VERSION 5.7 ;
  NOWIREEXTENSIONATPIN ON ;
  DIVIDERCHAR "/" ;
  BUSBITCHARS "[]" ;
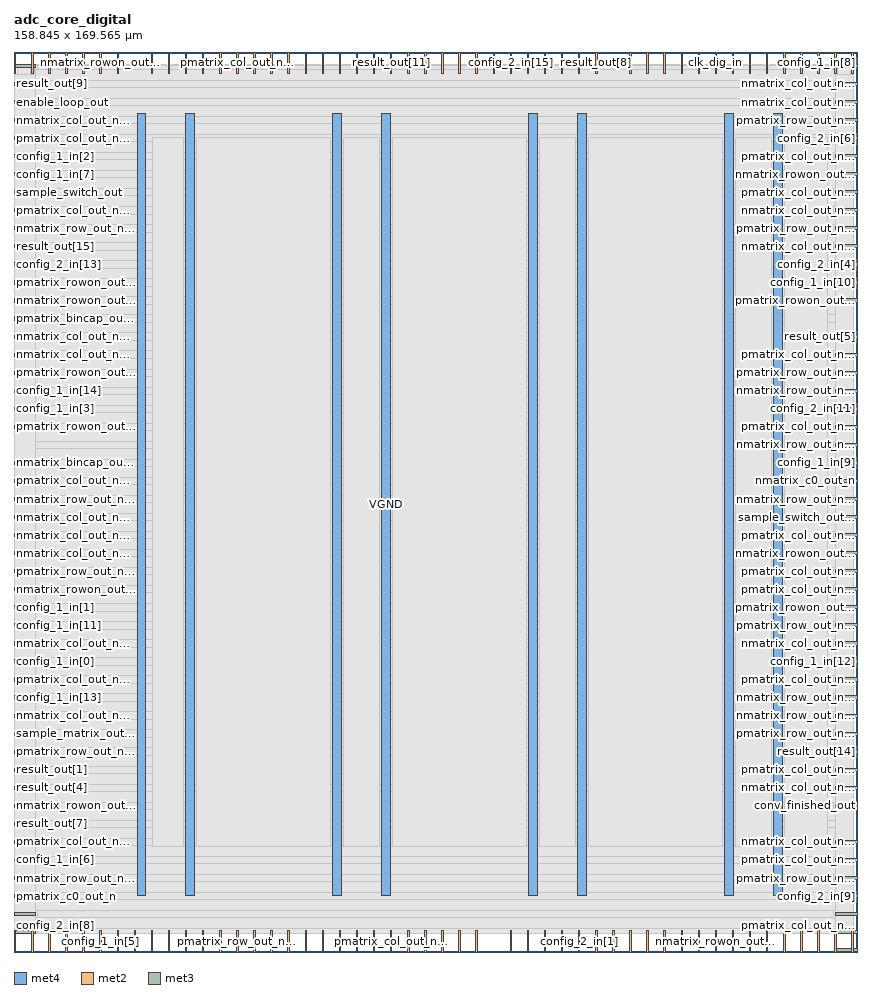
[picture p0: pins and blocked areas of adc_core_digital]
MACRO adc_core_digital
  CLASS BLOCK ;
  FOREIGN adc_core_digital ;
  ORIGIN 0.000 0.000 ;
  SIZE 158.845 BY 169.565 ;
  PIN VGND
    DIRECTION INOUT ;
    USE GROUND ;
    PORT
      LAYER met4 ;
        RECT 32.400 10.640 34.000 158.000 ;
    END
    PORT
      LAYER met4 ;
        RECT 69.315 10.640 70.915 158.000 ;
    END
    PORT
      LAYER met4 ;
        RECT 106.230 10.640 107.830 158.000 ;
    END
    PORT
      LAYER met4 ;
        RECT 143.145 10.640 144.745 158.000 ;
    END
  END VGND
  PIN VPWR
    DIRECTION INOUT ;
    USE POWER ;
    PORT
      LAYER met4 ;
        RECT 23.175 10.640 24.775 158.000 ;
    END
    PORT
      LAYER met4 ;
        RECT 60.090 10.640 61.690 158.000 ;
    END
    PORT
      LAYER met4 ;
        RECT 97.005 10.640 98.605 158.000 ;
    END
    PORT
      LAYER met4 ;
        RECT 133.920 10.640 135.520 158.000 ;
    END
  END VPWR
  PIN clk_dig_in
    DIRECTION INPUT ;
    USE SIGNAL ;
    PORT
      LAYER met2 ;
        RECT 132.110 165.565 132.390 169.565 ;
    END
  END clk_dig_in
  PIN comparator_in
    DIRECTION INPUT ;
    USE SIGNAL ;
    PORT
      LAYER met2 ;
        RECT 51.610 165.565 51.890 169.565 ;
    END
  END comparator_in
  PIN config_1_in[0]
    DIRECTION INPUT ;
    USE SIGNAL ;
    PORT
      LAYER met3 ;
        RECT 0.000 54.440 4.000 55.040 ;
    END
  END config_1_in[0]
  PIN config_1_in[10]
    DIRECTION INPUT ;
    USE SIGNAL ;
    PORT
      LAYER met3 ;
        RECT 154.845 125.840 158.845 126.440 ;
    END
  END config_1_in[10]
  PIN config_1_in[11]
    DIRECTION INPUT ;
    USE SIGNAL ;
    PORT
      LAYER met3 ;
        RECT 0.000 61.240 4.000 61.840 ;
    END
  END config_1_in[11]
  PIN config_1_in[12]
    DIRECTION INPUT ;
    USE SIGNAL ;
    PORT
      LAYER met3 ;
        RECT 154.845 54.440 158.845 55.040 ;
    END
  END config_1_in[12]
  PIN config_1_in[13]
    DIRECTION INPUT ;
    USE SIGNAL ;
    PORT
      LAYER met3 ;
        RECT 0.000 47.640 4.000 48.240 ;
    END
  END config_1_in[13]
  PIN config_1_in[14]
    DIRECTION INPUT ;
    USE SIGNAL ;
    PORT
      LAYER met3 ;
        RECT 0.000 105.440 4.000 106.040 ;
    END
  END config_1_in[14]
  PIN config_1_in[15]
    DIRECTION INPUT ;
    USE SIGNAL ;
    PORT
      LAYER met2 ;
        RECT 35.510 165.565 35.790 169.565 ;
    END
  END config_1_in[15]
  PIN config_1_in[1]
    DIRECTION INPUT ;
    USE SIGNAL ;
    PORT
      LAYER met3 ;
        RECT 0.000 64.640 4.000 65.240 ;
    END
  END config_1_in[1]
  PIN config_1_in[2]
    DIRECTION INPUT ;
    USE SIGNAL ;
    PORT
      LAYER met3 ;
        RECT 0.000 149.640 4.000 150.240 ;
    END
  END config_1_in[2]
  PIN config_1_in[3]
    DIRECTION INPUT ;
    USE SIGNAL ;
    PORT
      LAYER met3 ;
        RECT 0.000 102.040 4.000 102.640 ;
    END
  END config_1_in[3]
  PIN config_1_in[4]
    DIRECTION INPUT ;
    USE SIGNAL ;
    PORT
      LAYER met2 ;
        RECT 29.070 165.565 29.350 169.565 ;
    END
  END config_1_in[4]
  PIN config_1_in[5]
    DIRECTION INPUT ;
    USE SIGNAL ;
    PORT
      LAYER met2 ;
        RECT 16.190 0.000 16.470 4.000 ;
    END
  END config_1_in[5]
  PIN config_1_in[6]
    DIRECTION INPUT ;
    USE SIGNAL ;
    PORT
      LAYER met3 ;
        RECT 0.000 17.040 4.000 17.640 ;
    END
  END config_1_in[6]
  PIN config_1_in[7]
    DIRECTION INPUT ;
    USE SIGNAL ;
    PORT
      LAYER met3 ;
        RECT 0.000 146.240 4.000 146.840 ;
    END
  END config_1_in[7]
  PIN config_1_in[8]
    DIRECTION INPUT ;
    USE SIGNAL ;
    PORT
      LAYER met2 ;
        RECT 154.650 165.565 154.930 169.565 ;
    END
  END config_1_in[8]
  PIN config_1_in[9]
    DIRECTION INPUT ;
    USE SIGNAL ;
    PORT
      LAYER met3 ;
        RECT 154.845 91.840 158.845 92.440 ;
    END
  END config_1_in[9]
  PIN config_2_in[0]
    DIRECTION INPUT ;
    USE SIGNAL ;
    PORT
      LAYER met2 ;
        RECT 38.730 0.000 39.010 4.000 ;
    END
  END config_2_in[0]
  PIN config_2_in[10]
    DIRECTION INPUT ;
    USE SIGNAL ;
    PORT
      LAYER met2 ;
        RECT 64.490 165.565 64.770 169.565 ;
    END
  END config_2_in[10]
  PIN config_2_in[11]
    DIRECTION INPUT ;
    USE SIGNAL ;
    PORT
      LAYER met3 ;
        RECT 154.845 102.040 158.845 102.640 ;
    END
  END config_2_in[11]
  PIN config_2_in[12]
    DIRECTION INPUT ;
    USE SIGNAL ;
    PORT
      LAYER met3 ;
        RECT 154.845 0.040 158.845 0.640 ;
    END
  END config_2_in[12]
  PIN config_2_in[13]
    DIRECTION INPUT ;
    USE SIGNAL ;
    PORT
      LAYER met3 ;
        RECT 0.000 129.240 4.000 129.840 ;
    END
  END config_2_in[13]
  PIN config_2_in[14]
    DIRECTION INPUT ;
    USE SIGNAL ;
    PORT
      LAYER met2 ;
        RECT 51.610 0.000 51.890 4.000 ;
    END
  END config_2_in[14]
  PIN config_2_in[15]
    DIRECTION INPUT ;
    USE SIGNAL ;
    PORT
      LAYER met2 ;
        RECT 93.470 165.565 93.750 169.565 ;
    END
  END config_2_in[15]
  PIN config_2_in[1]
    DIRECTION INPUT ;
    USE SIGNAL ;
    PORT
      LAYER met2 ;
        RECT 106.350 0.000 106.630 4.000 ;
    END
  END config_2_in[1]
  PIN config_2_in[2]
    DIRECTION INPUT ;
    USE SIGNAL ;
    PORT
      LAYER met2 ;
        RECT 83.810 165.565 84.090 169.565 ;
    END
  END config_2_in[2]
  PIN config_2_in[3]
    DIRECTION INPUT ;
    USE SIGNAL ;
    PORT
      LAYER met2 ;
        RECT 151.430 0.000 151.710 4.000 ;
    END
  END config_2_in[3]
  PIN config_2_in[4]
    DIRECTION INPUT ;
    USE SIGNAL ;
    PORT
      LAYER met3 ;
        RECT 154.845 129.240 158.845 129.840 ;
    END
  END config_2_in[4]
  PIN config_2_in[5]
    DIRECTION INPUT ;
    USE SIGNAL ;
    PORT
      LAYER met2 ;
        RECT 67.710 165.565 67.990 169.565 ;
    END
  END config_2_in[5]
  PIN config_2_in[6]
    DIRECTION INPUT ;
    USE SIGNAL ;
    PORT
      LAYER met3 ;
        RECT 154.845 153.040 158.845 153.640 ;
    END
  END config_2_in[6]
  PIN config_2_in[7]
    DIRECTION INPUT ;
    USE SIGNAL ;
    PORT
      LAYER met2 ;
        RECT 135.330 165.565 135.610 169.565 ;
    END
  END config_2_in[7]
  PIN config_2_in[8]
    DIRECTION INPUT ;
    USE SIGNAL ;
    PORT
      LAYER met3 ;
        RECT 0.000 3.440 4.000 4.040 ;
    END
  END config_2_in[8]
  PIN config_2_in[9]
    DIRECTION INPUT ;
    USE SIGNAL ;
    PORT
      LAYER met3 ;
        RECT 154.845 10.240 158.845 10.840 ;
    END
  END config_2_in[9]
  PIN conv_finished_out
    DIRECTION OUTPUT TRISTATE ;
    USE SIGNAL ;
    PORT
      LAYER met3 ;
        RECT 154.845 27.240 158.845 27.840 ;
    END
  END conv_finished_out
  PIN enable_loop_out
    DIRECTION OUTPUT TRISTATE ;
    USE SIGNAL ;
    PORT
      LAYER met3 ;
        RECT 0.000 159.840 4.000 160.440 ;
    END
  END enable_loop_out
  PIN nmatrix_bincap_out_n[0]
    DIRECTION OUTPUT TRISTATE ;
    USE SIGNAL ;
    PORT
      LAYER met2 ;
        RECT 6.530 165.565 6.810 169.565 ;
    END
  END nmatrix_bincap_out_n[0]
  PIN nmatrix_bincap_out_n[1]
    DIRECTION OUTPUT TRISTATE ;
    USE SIGNAL ;
    PORT
      LAYER met3 ;
        RECT 0.000 91.840 4.000 92.440 ;
    END
  END nmatrix_bincap_out_n[1]
  PIN nmatrix_bincap_out_n[2]
    DIRECTION OUTPUT TRISTATE ;
    USE SIGNAL ;
    PORT
      LAYER met3 ;
        RECT 0.000 6.840 4.000 7.440 ;
    END
  END nmatrix_bincap_out_n[2]
  PIN nmatrix_c0_out_n
    DIRECTION OUTPUT TRISTATE ;
    USE SIGNAL ;
    PORT
      LAYER met3 ;
        RECT 154.845 88.440 158.845 89.040 ;
    END
  END nmatrix_c0_out_n
  PIN nmatrix_col_out_n[0]
    DIRECTION OUTPUT TRISTATE ;
    USE SIGNAL ;
    PORT
      LAYER met3 ;
        RECT 0.000 81.640 4.000 82.240 ;
    END
  END nmatrix_col_out_n[0]
  PIN nmatrix_col_out_n[10]
    DIRECTION OUTPUT TRISTATE ;
    USE SIGNAL ;
    PORT
      LAYER met3 ;
        RECT 0.000 166.640 4.000 167.240 ;
    END
  END nmatrix_col_out_n[10]
  PIN nmatrix_col_out_n[11]
    DIRECTION OUTPUT TRISTATE ;
    USE SIGNAL ;
    PORT
      LAYER met3 ;
        RECT 0.000 156.440 4.000 157.040 ;
    END
  END nmatrix_col_out_n[11]
  PIN nmatrix_col_out_n[12]
    DIRECTION OUTPUT TRISTATE ;
    USE SIGNAL ;
    PORT
      LAYER met2 ;
        RECT 144.990 0.000 145.270 4.000 ;
    END
  END nmatrix_col_out_n[12]
  PIN nmatrix_col_out_n[13]
    DIRECTION OUTPUT TRISTATE ;
    USE SIGNAL ;
    PORT
      LAYER met3 ;
        RECT 0.000 112.240 4.000 112.840 ;
    END
  END nmatrix_col_out_n[13]
  PIN nmatrix_col_out_n[14]
    DIRECTION OUTPUT TRISTATE ;
    USE SIGNAL ;
    PORT
      LAYER met2 ;
        RECT 141.770 165.565 142.050 169.565 ;
    END
  END nmatrix_col_out_n[14]
  PIN nmatrix_col_out_n[15]
    DIRECTION OUTPUT TRISTATE ;
    USE SIGNAL ;
    PORT
      LAYER met3 ;
        RECT 154.845 57.840 158.845 58.440 ;
    END
  END nmatrix_col_out_n[15]
  PIN nmatrix_col_out_n[16]
    DIRECTION OUTPUT TRISTATE ;
    USE SIGNAL ;
    PORT
      LAYER met3 ;
        RECT 0.000 115.640 4.000 116.240 ;
    END
  END nmatrix_col_out_n[16]
  PIN nmatrix_col_out_n[17]
    DIRECTION OUTPUT TRISTATE ;
    USE SIGNAL ;
    PORT
      LAYER met3 ;
        RECT 154.845 20.440 158.845 21.040 ;
    END
  END nmatrix_col_out_n[17]
  PIN nmatrix_col_out_n[18]
    DIRECTION OUTPUT TRISTATE ;
    USE SIGNAL ;
    PORT
      LAYER met2 ;
        RECT 45.170 0.000 45.450 4.000 ;
    END
  END nmatrix_col_out_n[18]
  PIN nmatrix_col_out_n[19]
    DIRECTION OUTPUT TRISTATE ;
    USE SIGNAL ;
    PORT
      LAYER met3 ;
        RECT 0.000 44.240 4.000 44.840 ;
    END
  END nmatrix_col_out_n[19]
  PIN nmatrix_col_out_n[1]
    DIRECTION OUTPUT TRISTATE ;
    USE SIGNAL ;
    PORT
      LAYER met3 ;
        RECT 0.000 57.840 4.000 58.440 ;
    END
  END nmatrix_col_out_n[1]
  PIN nmatrix_col_out_n[20]
    DIRECTION OUTPUT TRISTATE ;
    USE SIGNAL ;
    PORT
      LAYER met3 ;
        RECT 154.845 132.640 158.845 133.240 ;
    END
  END nmatrix_col_out_n[20]
  PIN nmatrix_col_out_n[21]
    DIRECTION OUTPUT TRISTATE ;
    USE SIGNAL ;
    PORT
      LAYER met2 ;
        RECT 48.390 165.565 48.670 169.565 ;
    END
  END nmatrix_col_out_n[21]
  PIN nmatrix_col_out_n[22]
    DIRECTION OUTPUT TRISTATE ;
    USE SIGNAL ;
    PORT
      LAYER met3 ;
        RECT 154.845 163.240 158.845 163.840 ;
    END
  END nmatrix_col_out_n[22]
  PIN nmatrix_col_out_n[23]
    DIRECTION OUTPUT TRISTATE ;
    USE SIGNAL ;
    PORT
      LAYER met3 ;
        RECT 0.000 78.240 4.000 78.840 ;
    END
  END nmatrix_col_out_n[23]
  PIN nmatrix_col_out_n[24]
    DIRECTION OUTPUT TRISTATE ;
    USE SIGNAL ;
    PORT
      LAYER met2 ;
        RECT 12.970 0.000 13.250 4.000 ;
    END
  END nmatrix_col_out_n[24]
  PIN nmatrix_col_out_n[25]
    DIRECTION OUTPUT TRISTATE ;
    USE SIGNAL ;
    PORT
      LAYER met3 ;
        RECT 0.000 74.840 4.000 75.440 ;
    END
  END nmatrix_col_out_n[25]
  PIN nmatrix_col_out_n[26]
    DIRECTION OUTPUT TRISTATE ;
    USE SIGNAL ;
    PORT
      LAYER met2 ;
        RECT 77.370 165.565 77.650 169.565 ;
    END
  END nmatrix_col_out_n[26]
  PIN nmatrix_col_out_n[27]
    DIRECTION OUTPUT TRISTATE ;
    USE SIGNAL ;
    PORT
      LAYER met3 ;
        RECT 154.845 139.440 158.845 140.040 ;
    END
  END nmatrix_col_out_n[27]
  PIN nmatrix_col_out_n[28]
    DIRECTION OUTPUT TRISTATE ;
    USE SIGNAL ;
    PORT
      LAYER met2 ;
        RECT 54.830 165.565 55.110 169.565 ;
    END
  END nmatrix_col_out_n[28]
  PIN nmatrix_col_out_n[29]
    DIRECTION OUTPUT TRISTATE ;
    USE SIGNAL ;
    PORT
      LAYER met3 ;
        RECT 154.845 159.840 158.845 160.440 ;
    END
  END nmatrix_col_out_n[29]
  PIN nmatrix_col_out_n[2]
    DIRECTION OUTPUT TRISTATE ;
    USE SIGNAL ;
    PORT
      LAYER met2 ;
        RECT 9.750 165.565 10.030 169.565 ;
    END
  END nmatrix_col_out_n[2]
  PIN nmatrix_col_out_n[30]
    DIRECTION OUTPUT TRISTATE ;
    USE SIGNAL ;
    PORT
      LAYER met2 ;
        RECT 125.670 0.000 125.950 4.000 ;
    END
  END nmatrix_col_out_n[30]
  PIN nmatrix_col_out_n[31]
    DIRECTION OUTPUT TRISTATE ;
    USE SIGNAL ;
    PORT
      LAYER met2 ;
        RECT 138.550 165.565 138.830 169.565 ;
    END
  END nmatrix_col_out_n[31]
  PIN nmatrix_col_out_n[3]
    DIRECTION OUTPUT TRISTATE ;
    USE SIGNAL ;
    PORT
      LAYER met2 ;
        RECT 25.850 165.565 26.130 169.565 ;
    END
  END nmatrix_col_out_n[3]
  PIN nmatrix_col_out_n[4]
    DIRECTION OUTPUT TRISTATE ;
    USE SIGNAL ;
    PORT
      LAYER met2 ;
        RECT 74.150 0.000 74.430 4.000 ;
    END
  END nmatrix_col_out_n[4]
  PIN nmatrix_col_out_n[5]
    DIRECTION OUTPUT TRISTATE ;
    USE SIGNAL ;
    PORT
      LAYER met2 ;
        RECT 128.890 0.000 129.170 4.000 ;
    END
  END nmatrix_col_out_n[5]
  PIN nmatrix_col_out_n[6]
    DIRECTION OUTPUT TRISTATE ;
    USE SIGNAL ;
    PORT
      LAYER met3 ;
        RECT 154.845 30.640 158.845 31.240 ;
    END
  END nmatrix_col_out_n[6]
  PIN nmatrix_col_out_n[7]
    DIRECTION OUTPUT TRISTATE ;
    USE SIGNAL ;
    PORT
      LAYER met2 ;
        RECT 122.450 0.000 122.730 4.000 ;
    END
  END nmatrix_col_out_n[7]
  PIN nmatrix_col_out_n[8]
    DIRECTION OUTPUT TRISTATE ;
    USE SIGNAL ;
    PORT
      LAYER met2 ;
        RECT 61.270 0.000 61.550 4.000 ;
    END
  END nmatrix_col_out_n[8]
  PIN nmatrix_col_out_n[9]
    DIRECTION OUTPUT TRISTATE ;
    USE SIGNAL ;
    PORT
      LAYER met3 ;
        RECT 154.845 166.640 158.845 167.240 ;
    END
  END nmatrix_col_out_n[9]
  PIN nmatrix_row_out_n[0]
    DIRECTION OUTPUT TRISTATE ;
    USE SIGNAL ;
    PORT
      LAYER met3 ;
        RECT 0.000 85.040 4.000 85.640 ;
    END
  END nmatrix_row_out_n[0]
  PIN nmatrix_row_out_n[10]
    DIRECTION OUTPUT TRISTATE ;
    USE SIGNAL ;
    PORT
      LAYER met3 ;
        RECT 154.845 47.640 158.845 48.240 ;
    END
  END nmatrix_row_out_n[10]
  PIN nmatrix_row_out_n[11]
    DIRECTION OUTPUT TRISTATE ;
    USE SIGNAL ;
    PORT
      LAYER met2 ;
        RECT 77.370 0.000 77.650 4.000 ;
    END
  END nmatrix_row_out_n[11]
  PIN nmatrix_row_out_n[12]
    DIRECTION OUTPUT TRISTATE ;
    USE SIGNAL ;
    PORT
      LAYER met3 ;
        RECT 154.845 85.040 158.845 85.640 ;
    END
  END nmatrix_row_out_n[12]
  PIN nmatrix_row_out_n[13]
    DIRECTION OUTPUT TRISTATE ;
    USE SIGNAL ;
    PORT
      LAYER met2 ;
        RECT 122.450 165.565 122.730 169.565 ;
    END
  END nmatrix_row_out_n[13]
  PIN nmatrix_row_out_n[14]
    DIRECTION OUTPUT TRISTATE ;
    USE SIGNAL ;
    PORT
      LAYER met2 ;
        RECT 45.170 165.565 45.450 169.565 ;
    END
  END nmatrix_row_out_n[14]
  PIN nmatrix_row_out_n[15]
    DIRECTION OUTPUT TRISTATE ;
    USE SIGNAL ;
    PORT
      LAYER met2 ;
        RECT 48.390 0.000 48.670 4.000 ;
    END
  END nmatrix_row_out_n[15]
  PIN nmatrix_row_out_n[1]
    DIRECTION OUTPUT TRISTATE ;
    USE SIGNAL ;
    PORT
      LAYER met3 ;
        RECT 0.000 136.040 4.000 136.640 ;
    END
  END nmatrix_row_out_n[1]
  PIN nmatrix_row_out_n[2]
    DIRECTION OUTPUT TRISTATE ;
    USE SIGNAL ;
    PORT
      LAYER met2 ;
        RECT 22.630 0.000 22.910 4.000 ;
    END
  END nmatrix_row_out_n[2]
  PIN nmatrix_row_out_n[3]
    DIRECTION OUTPUT TRISTATE ;
    USE SIGNAL ;
    PORT
      LAYER met2 ;
        RECT 83.810 0.000 84.090 4.000 ;
    END
  END nmatrix_row_out_n[3]
  PIN nmatrix_row_out_n[4]
    DIRECTION OUTPUT TRISTATE ;
    USE SIGNAL ;
    PORT
      LAYER met3 ;
        RECT 154.845 95.240 158.845 95.840 ;
    END
  END nmatrix_row_out_n[4]
  PIN nmatrix_row_out_n[5]
    DIRECTION OUTPUT TRISTATE ;
    USE SIGNAL ;
    PORT
      LAYER met3 ;
        RECT 154.845 44.240 158.845 44.840 ;
    END
  END nmatrix_row_out_n[5]
  PIN nmatrix_row_out_n[6]
    DIRECTION OUTPUT TRISTATE ;
    USE SIGNAL ;
    PORT
      LAYER met2 ;
        RECT 99.910 165.565 100.190 169.565 ;
    END
  END nmatrix_row_out_n[6]
  PIN nmatrix_row_out_n[7]
    DIRECTION OUTPUT TRISTATE ;
    USE SIGNAL ;
    PORT
      LAYER met3 ;
        RECT 154.845 105.440 158.845 106.040 ;
    END
  END nmatrix_row_out_n[7]
  PIN nmatrix_row_out_n[8]
    DIRECTION OUTPUT TRISTATE ;
    USE SIGNAL ;
    PORT
      LAYER met2 ;
        RECT 119.230 165.565 119.510 169.565 ;
    END
  END nmatrix_row_out_n[8]
  PIN nmatrix_row_out_n[9]
    DIRECTION OUTPUT TRISTATE ;
    USE SIGNAL ;
    PORT
      LAYER met3 ;
        RECT 0.000 13.640 4.000 14.240 ;
    END
  END nmatrix_row_out_n[9]
  PIN nmatrix_rowon_out_n[0]
    DIRECTION OUTPUT TRISTATE ;
    USE SIGNAL ;
    PORT
      LAYER met3 ;
        RECT 0.000 122.440 4.000 123.040 ;
    END
  END nmatrix_rowon_out_n[0]
  PIN nmatrix_rowon_out_n[10]
    DIRECTION OUTPUT TRISTATE ;
    USE SIGNAL ;
    PORT
      LAYER met2 ;
        RECT 132.110 0.000 132.390 4.000 ;
    END
  END nmatrix_rowon_out_n[10]
  PIN nmatrix_rowon_out_n[11]
    DIRECTION OUTPUT TRISTATE ;
    USE SIGNAL ;
    PORT
      LAYER met3 ;
        RECT 154.845 74.840 158.845 75.440 ;
    END
  END nmatrix_rowon_out_n[11]
  PIN nmatrix_rowon_out_n[12]
    DIRECTION OUTPUT TRISTATE ;
    USE SIGNAL ;
    PORT
      LAYER met2 ;
        RECT 144.990 165.565 145.270 169.565 ;
    END
  END nmatrix_rowon_out_n[12]
  PIN nmatrix_rowon_out_n[13]
    DIRECTION OUTPUT TRISTATE ;
    USE SIGNAL ;
    PORT
      LAYER met3 ;
        RECT 154.845 146.240 158.845 146.840 ;
    END
  END nmatrix_rowon_out_n[13]
  PIN nmatrix_rowon_out_n[14]
    DIRECTION OUTPUT TRISTATE ;
    USE SIGNAL ;
    PORT
      LAYER met2 ;
        RECT 6.530 0.000 6.810 4.000 ;
    END
  END nmatrix_rowon_out_n[14]
  PIN nmatrix_rowon_out_n[15]
    DIRECTION OUTPUT TRISTATE ;
    USE SIGNAL ;
    PORT
      LAYER met2 ;
        RECT 54.830 0.000 55.110 4.000 ;
    END
  END nmatrix_rowon_out_n[15]
  PIN nmatrix_rowon_out_n[1]
    DIRECTION OUTPUT TRISTATE ;
    USE SIGNAL ;
    PORT
      LAYER met2 ;
        RECT 116.010 165.565 116.290 169.565 ;
    END
  END nmatrix_rowon_out_n[1]
  PIN nmatrix_rowon_out_n[2]
    DIRECTION OUTPUT TRISTATE ;
    USE SIGNAL ;
    PORT
      LAYER met2 ;
        RECT 16.190 165.565 16.470 169.565 ;
    END
  END nmatrix_rowon_out_n[2]
  PIN nmatrix_rowon_out_n[3]
    DIRECTION OUTPUT TRISTATE ;
    USE SIGNAL ;
    PORT
      LAYER met2 ;
        RECT 64.490 0.000 64.770 4.000 ;
    END
  END nmatrix_rowon_out_n[3]
  PIN nmatrix_rowon_out_n[4]
    DIRECTION OUTPUT TRISTATE ;
    USE SIGNAL ;
    PORT
      LAYER met3 ;
        RECT 154.845 6.840 158.845 7.440 ;
    END
  END nmatrix_rowon_out_n[4]
  PIN nmatrix_rowon_out_n[5]
    DIRECTION OUTPUT TRISTATE ;
    USE SIGNAL ;
    PORT
      LAYER met2 ;
        RECT 138.550 0.000 138.830 4.000 ;
    END
  END nmatrix_rowon_out_n[5]
  PIN nmatrix_rowon_out_n[6]
    DIRECTION OUTPUT TRISTATE ;
    USE SIGNAL ;
    PORT
      LAYER met2 ;
        RECT 103.130 0.000 103.410 4.000 ;
    END
  END nmatrix_rowon_out_n[6]
  PIN nmatrix_rowon_out_n[7]
    DIRECTION OUTPUT TRISTATE ;
    USE SIGNAL ;
    PORT
      LAYER met3 ;
        RECT 0.000 68.040 4.000 68.640 ;
    END
  END nmatrix_rowon_out_n[7]
  PIN nmatrix_rowon_out_n[8]
    DIRECTION OUTPUT TRISTATE ;
    USE SIGNAL ;
    PORT
      LAYER met3 ;
        RECT 0.000 27.240 4.000 27.840 ;
    END
  END nmatrix_rowon_out_n[8]
  PIN nmatrix_rowon_out_n[9]
    DIRECTION OUTPUT TRISTATE ;
    USE SIGNAL ;
    PORT
      LAYER met2 ;
        RECT 125.670 165.565 125.950 169.565 ;
    END
  END nmatrix_rowon_out_n[9]
  PIN pmatrix_bincap_out_n[0]
    DIRECTION OUTPUT TRISTATE ;
    USE SIGNAL ;
    PORT
      LAYER met2 ;
        RECT 38.730 165.565 39.010 169.565 ;
    END
  END pmatrix_bincap_out_n[0]
  PIN pmatrix_bincap_out_n[1]
    DIRECTION OUTPUT TRISTATE ;
    USE SIGNAL ;
    PORT
      LAYER met2 ;
        RECT 135.330 0.000 135.610 4.000 ;
    END
  END pmatrix_bincap_out_n[1]
  PIN pmatrix_bincap_out_n[2]
    DIRECTION OUTPUT TRISTATE ;
    USE SIGNAL ;
    PORT
      LAYER met3 ;
        RECT 0.000 119.040 4.000 119.640 ;
    END
  END pmatrix_bincap_out_n[2]
  PIN pmatrix_c0_out_n
    DIRECTION OUTPUT TRISTATE ;
    USE SIGNAL ;
    PORT
      LAYER met3 ;
        RECT 0.000 10.240 4.000 10.840 ;
    END
  END pmatrix_c0_out_n
  PIN pmatrix_col_out_n[0]
    DIRECTION OUTPUT TRISTATE ;
    USE SIGNAL ;
    PORT
      LAYER met3 ;
        RECT 0.000 51.040 4.000 51.640 ;
    END
  END pmatrix_col_out_n[0]
  PIN pmatrix_col_out_n[10]
    DIRECTION OUTPUT TRISTATE ;
    USE SIGNAL ;
    PORT
      LAYER met3 ;
        RECT 154.845 149.640 158.845 150.240 ;
    END
  END pmatrix_col_out_n[10]
  PIN pmatrix_col_out_n[11]
    DIRECTION OUTPUT TRISTATE ;
    USE SIGNAL ;
    PORT
      LAYER met3 ;
        RECT 154.845 17.040 158.845 17.640 ;
    END
  END pmatrix_col_out_n[11]
  PIN pmatrix_col_out_n[12]
    DIRECTION OUTPUT TRISTATE ;
    USE SIGNAL ;
    PORT
      LAYER met3 ;
        RECT 154.845 68.040 158.845 68.640 ;
    END
  END pmatrix_col_out_n[12]
  PIN pmatrix_col_out_n[13]
    DIRECTION OUTPUT TRISTATE ;
    USE SIGNAL ;
    PORT
      LAYER met2 ;
        RECT 3.310 165.565 3.590 169.565 ;
    END
  END pmatrix_col_out_n[13]
  PIN pmatrix_col_out_n[14]
    DIRECTION OUTPUT TRISTATE ;
    USE SIGNAL ;
    PORT
      LAYER met3 ;
        RECT 154.845 98.640 158.845 99.240 ;
    END
  END pmatrix_col_out_n[14]
  PIN pmatrix_col_out_n[15]
    DIRECTION OUTPUT TRISTATE ;
    USE SIGNAL ;
    PORT
      LAYER met3 ;
        RECT 154.845 3.440 158.845 4.040 ;
    END
  END pmatrix_col_out_n[15]
  PIN pmatrix_col_out_n[16]
    DIRECTION OUTPUT TRISTATE ;
    USE SIGNAL ;
    PORT
      LAYER met2 ;
        RECT 90.250 165.565 90.530 169.565 ;
    END
  END pmatrix_col_out_n[16]
  PIN pmatrix_col_out_n[17]
    DIRECTION OUTPUT TRISTATE ;
    USE SIGNAL ;
    PORT
      LAYER met2 ;
        RECT 41.950 165.565 42.230 169.565 ;
    END
  END pmatrix_col_out_n[17]
  PIN pmatrix_col_out_n[18]
    DIRECTION OUTPUT TRISTATE ;
    USE SIGNAL ;
    PORT
      LAYER met2 ;
        RECT 87.030 0.000 87.310 4.000 ;
    END
  END pmatrix_col_out_n[18]
  PIN pmatrix_col_out_n[19]
    DIRECTION OUTPUT TRISTATE ;
    USE SIGNAL ;
    PORT
      LAYER met2 ;
        RECT 35.510 0.000 35.790 4.000 ;
    END
  END pmatrix_col_out_n[19]
  PIN pmatrix_col_out_n[1]
    DIRECTION OUTPUT TRISTATE ;
    USE SIGNAL ;
    PORT
      LAYER met2 ;
        RECT 58.050 165.565 58.330 169.565 ;
    END
  END pmatrix_col_out_n[1]
  PIN pmatrix_col_out_n[20]
    DIRECTION OUTPUT TRISTATE ;
    USE SIGNAL ;
    PORT
      LAYER met2 ;
        RECT 119.230 0.000 119.510 4.000 ;
    END
  END pmatrix_col_out_n[20]
  PIN pmatrix_col_out_n[21]
    DIRECTION OUTPUT TRISTATE ;
    USE SIGNAL ;
    PORT
      LAYER met2 ;
        RECT 154.650 0.000 154.930 4.000 ;
    END
  END pmatrix_col_out_n[21]
  PIN pmatrix_col_out_n[22]
    DIRECTION OUTPUT TRISTATE ;
    USE SIGNAL ;
    PORT
      LAYER met2 ;
        RECT 151.430 165.565 151.710 169.565 ;
    END
  END pmatrix_col_out_n[22]
  PIN pmatrix_col_out_n[23]
    DIRECTION OUTPUT TRISTATE ;
    USE SIGNAL ;
    PORT
      LAYER met3 ;
        RECT 154.845 71.440 158.845 72.040 ;
    END
  END pmatrix_col_out_n[23]
  PIN pmatrix_col_out_n[24]
    DIRECTION OUTPUT TRISTATE ;
    USE SIGNAL ;
    PORT
      LAYER met2 ;
        RECT 61.270 165.565 61.550 169.565 ;
    END
  END pmatrix_col_out_n[24]
  PIN pmatrix_col_out_n[25]
    DIRECTION OUTPUT TRISTATE ;
    USE SIGNAL ;
    PORT
      LAYER met2 ;
        RECT 87.030 165.565 87.310 169.565 ;
    END
  END pmatrix_col_out_n[25]
  PIN pmatrix_col_out_n[26]
    DIRECTION OUTPUT TRISTATE ;
    USE SIGNAL ;
    PORT
      LAYER met2 ;
        RECT 80.590 165.565 80.870 169.565 ;
    END
  END pmatrix_col_out_n[26]
  PIN pmatrix_col_out_n[27]
    DIRECTION OUTPUT TRISTATE ;
    USE SIGNAL ;
    PORT
      LAYER met3 ;
        RECT 0.000 88.440 4.000 89.040 ;
    END
  END pmatrix_col_out_n[27]
  PIN pmatrix_col_out_n[28]
    DIRECTION OUTPUT TRISTATE ;
    USE SIGNAL ;
    PORT
      LAYER met2 ;
        RECT 25.850 0.000 26.130 4.000 ;
    END
  END pmatrix_col_out_n[28]
  PIN pmatrix_col_out_n[29]
    DIRECTION OUTPUT TRISTATE ;
    USE SIGNAL ;
    PORT
      LAYER met3 ;
        RECT 154.845 34.040 158.845 34.640 ;
    END
  END pmatrix_col_out_n[29]
  PIN pmatrix_col_out_n[2]
    DIRECTION OUTPUT TRISTATE ;
    USE SIGNAL ;
    PORT
      LAYER met2 ;
        RECT 70.930 0.000 71.210 4.000 ;
    END
  END pmatrix_col_out_n[2]
  PIN pmatrix_col_out_n[30]
    DIRECTION OUTPUT TRISTATE ;
    USE SIGNAL ;
    PORT
      LAYER met3 ;
        RECT 154.845 142.840 158.845 143.440 ;
    END
  END pmatrix_col_out_n[30]
  PIN pmatrix_col_out_n[31]
    DIRECTION OUTPUT TRISTATE ;
    USE SIGNAL ;
    PORT
      LAYER met3 ;
        RECT 0.000 139.440 4.000 140.040 ;
    END
  END pmatrix_col_out_n[31]
  PIN pmatrix_col_out_n[3]
    DIRECTION OUTPUT TRISTATE ;
    USE SIGNAL ;
    PORT
      LAYER met2 ;
        RECT 96.690 165.565 96.970 169.565 ;
    END
  END pmatrix_col_out_n[3]
  PIN pmatrix_col_out_n[4]
    DIRECTION OUTPUT TRISTATE ;
    USE SIGNAL ;
    PORT
      LAYER met3 ;
        RECT 0.000 153.040 4.000 153.640 ;
    END
  END pmatrix_col_out_n[4]
  PIN pmatrix_col_out_n[5]
    DIRECTION OUTPUT TRISTATE ;
    USE SIGNAL ;
    PORT
      LAYER met3 ;
        RECT 154.845 51.040 158.845 51.640 ;
    END
  END pmatrix_col_out_n[5]
  PIN pmatrix_col_out_n[6]
    DIRECTION OUTPUT TRISTATE ;
    USE SIGNAL ;
    PORT
      LAYER met3 ;
        RECT 154.845 112.240 158.845 112.840 ;
    END
  END pmatrix_col_out_n[6]
  PIN pmatrix_col_out_n[7]
    DIRECTION OUTPUT TRISTATE ;
    USE SIGNAL ;
    PORT
      LAYER met2 ;
        RECT 32.290 165.565 32.570 169.565 ;
    END
  END pmatrix_col_out_n[7]
  PIN pmatrix_col_out_n[8]
    DIRECTION OUTPUT TRISTATE ;
    USE SIGNAL ;
    PORT
      LAYER met3 ;
        RECT 154.845 78.240 158.845 78.840 ;
    END
  END pmatrix_col_out_n[8]
  PIN pmatrix_col_out_n[9]
    DIRECTION OUTPUT TRISTATE ;
    USE SIGNAL ;
    PORT
      LAYER met3 ;
        RECT 0.000 20.440 4.000 21.040 ;
    END
  END pmatrix_col_out_n[9]
  PIN pmatrix_row_out_n[0]
    DIRECTION OUTPUT TRISTATE ;
    USE SIGNAL ;
    PORT
      LAYER met3 ;
        RECT 0.000 37.440 4.000 38.040 ;
    END
  END pmatrix_row_out_n[0]
  PIN pmatrix_row_out_n[10]
    DIRECTION OUTPUT TRISTATE ;
    USE SIGNAL ;
    PORT
      LAYER met3 ;
        RECT 154.845 136.040 158.845 136.640 ;
    END
  END pmatrix_row_out_n[10]
  PIN pmatrix_row_out_n[11]
    DIRECTION OUTPUT TRISTATE ;
    USE SIGNAL ;
    PORT
      LAYER met2 ;
        RECT 106.350 165.565 106.630 169.565 ;
    END
  END pmatrix_row_out_n[11]
  PIN pmatrix_row_out_n[12]
    DIRECTION OUTPUT TRISTATE ;
    USE SIGNAL ;
    PORT
      LAYER met2 ;
        RECT 41.950 0.000 42.230 4.000 ;
    END
  END pmatrix_row_out_n[12]
  PIN pmatrix_row_out_n[13]
    DIRECTION OUTPUT TRISTATE ;
    USE SIGNAL ;
    PORT
      LAYER met3 ;
        RECT 154.845 61.240 158.845 61.840 ;
    END
  END pmatrix_row_out_n[13]
  PIN pmatrix_row_out_n[14]
    DIRECTION OUTPUT TRISTATE ;
    USE SIGNAL ;
    PORT
      LAYER met2 ;
        RECT 109.570 0.000 109.850 4.000 ;
    END
  END pmatrix_row_out_n[14]
  PIN pmatrix_row_out_n[15]
    DIRECTION OUTPUT TRISTATE ;
    USE SIGNAL ;
    PORT
      LAYER met3 ;
        RECT 154.845 13.640 158.845 14.240 ;
    END
  END pmatrix_row_out_n[15]
  PIN pmatrix_row_out_n[1]
    DIRECTION OUTPUT TRISTATE ;
    USE SIGNAL ;
    PORT
      LAYER met2 ;
        RECT 0.090 165.565 0.370 169.565 ;
    END
  END pmatrix_row_out_n[1]
  PIN pmatrix_row_out_n[2]
    DIRECTION OUTPUT TRISTATE ;
    USE SIGNAL ;
    PORT
      LAYER met2 ;
        RECT 141.770 0.000 142.050 4.000 ;
    END
  END pmatrix_row_out_n[2]
  PIN pmatrix_row_out_n[3]
    DIRECTION OUTPUT TRISTATE ;
    USE SIGNAL ;
    PORT
      LAYER met2 ;
        RECT 19.410 0.000 19.690 4.000 ;
    END
  END pmatrix_row_out_n[3]
  PIN pmatrix_row_out_n[4]
    DIRECTION OUTPUT TRISTATE ;
    USE SIGNAL ;
    PORT
      LAYER met2 ;
        RECT 67.710 0.000 67.990 4.000 ;
    END
  END pmatrix_row_out_n[4]
  PIN pmatrix_row_out_n[5]
    DIRECTION OUTPUT TRISTATE ;
    USE SIGNAL ;
    PORT
      LAYER met3 ;
        RECT 154.845 40.840 158.845 41.440 ;
    END
  END pmatrix_row_out_n[5]
  PIN pmatrix_row_out_n[6]
    DIRECTION OUTPUT TRISTATE ;
    USE SIGNAL ;
    PORT
      LAYER met3 ;
        RECT 154.845 156.440 158.845 157.040 ;
    END
  END pmatrix_row_out_n[6]
  PIN pmatrix_row_out_n[7]
    DIRECTION OUTPUT TRISTATE ;
    USE SIGNAL ;
    PORT
      LAYER met3 ;
        RECT 154.845 108.840 158.845 109.440 ;
    END
  END pmatrix_row_out_n[7]
  PIN pmatrix_row_out_n[8]
    DIRECTION OUTPUT TRISTATE ;
    USE SIGNAL ;
    PORT
      LAYER met2 ;
        RECT 148.210 0.000 148.490 4.000 ;
    END
  END pmatrix_row_out_n[8]
  PIN pmatrix_row_out_n[9]
    DIRECTION OUTPUT TRISTATE ;
    USE SIGNAL ;
    PORT
      LAYER met3 ;
        RECT 0.000 71.440 4.000 72.040 ;
    END
  END pmatrix_row_out_n[9]
  PIN pmatrix_rowon_out_n[0]
    DIRECTION OUTPUT TRISTATE ;
    USE SIGNAL ;
    PORT
      LAYER met3 ;
        RECT 154.845 64.640 158.845 65.240 ;
    END
  END pmatrix_rowon_out_n[0]
  PIN pmatrix_rowon_out_n[10]
    DIRECTION OUTPUT TRISTATE ;
    USE SIGNAL ;
    PORT
      LAYER met2 ;
        RECT 3.310 0.000 3.590 4.000 ;
    END
  END pmatrix_rowon_out_n[10]
  PIN pmatrix_rowon_out_n[11]
    DIRECTION OUTPUT TRISTATE ;
    USE SIGNAL ;
    PORT
      LAYER met3 ;
        RECT 154.845 122.440 158.845 123.040 ;
    END
  END pmatrix_rowon_out_n[11]
  PIN pmatrix_rowon_out_n[12]
    DIRECTION OUTPUT TRISTATE ;
    USE SIGNAL ;
    PORT
      LAYER met2 ;
        RECT 157.870 165.565 158.150 169.565 ;
    END
  END pmatrix_rowon_out_n[12]
  PIN pmatrix_rowon_out_n[13]
    DIRECTION OUTPUT TRISTATE ;
    USE SIGNAL ;
    PORT
      LAYER met2 ;
        RECT 157.870 0.000 158.150 4.000 ;
    END
  END pmatrix_rowon_out_n[13]
  PIN pmatrix_rowon_out_n[14]
    DIRECTION OUTPUT TRISTATE ;
    USE SIGNAL ;
    PORT
      LAYER met2 ;
        RECT 148.210 165.565 148.490 169.565 ;
    END
  END pmatrix_rowon_out_n[14]
  PIN pmatrix_rowon_out_n[15]
    DIRECTION OUTPUT TRISTATE ;
    USE SIGNAL ;
    PORT
      LAYER met2 ;
        RECT 96.690 0.000 96.970 4.000 ;
    END
  END pmatrix_rowon_out_n[15]
  PIN pmatrix_rowon_out_n[1]
    DIRECTION OUTPUT TRISTATE ;
    USE SIGNAL ;
    PORT
      LAYER met3 ;
        RECT 0.000 108.840 4.000 109.440 ;
    END
  END pmatrix_rowon_out_n[1]
  PIN pmatrix_rowon_out_n[2]
    DIRECTION OUTPUT TRISTATE ;
    USE SIGNAL ;
    PORT
      LAYER met2 ;
        RECT 99.910 0.000 100.190 4.000 ;
    END
  END pmatrix_rowon_out_n[2]
  PIN pmatrix_rowon_out_n[3]
    DIRECTION OUTPUT TRISTATE ;
    USE SIGNAL ;
    PORT
      LAYER met2 ;
        RECT 0.090 0.000 0.370 4.000 ;
    END
  END pmatrix_rowon_out_n[3]
  PIN pmatrix_rowon_out_n[4]
    DIRECTION OUTPUT TRISTATE ;
    USE SIGNAL ;
    PORT
      LAYER met2 ;
        RECT 116.010 0.000 116.290 4.000 ;
    END
  END pmatrix_rowon_out_n[4]
  PIN pmatrix_rowon_out_n[5]
    DIRECTION OUTPUT TRISTATE ;
    USE SIGNAL ;
    PORT
      LAYER met3 ;
        RECT 0.000 125.840 4.000 126.440 ;
    END
  END pmatrix_rowon_out_n[5]
  PIN pmatrix_rowon_out_n[6]
    DIRECTION OUTPUT TRISTATE ;
    USE SIGNAL ;
    PORT
      LAYER met2 ;
        RECT 12.970 165.565 13.250 169.565 ;
    END
  END pmatrix_rowon_out_n[6]
  PIN pmatrix_rowon_out_n[7]
    DIRECTION OUTPUT TRISTATE ;
    USE SIGNAL ;
    PORT
      LAYER met2 ;
        RECT 74.150 165.565 74.430 169.565 ;
    END
  END pmatrix_rowon_out_n[7]
  PIN pmatrix_rowon_out_n[8]
    DIRECTION OUTPUT TRISTATE ;
    USE SIGNAL ;
    PORT
      LAYER met3 ;
        RECT 0.000 98.640 4.000 99.240 ;
    END
  END pmatrix_rowon_out_n[8]
  PIN pmatrix_rowon_out_n[9]
    DIRECTION OUTPUT TRISTATE ;
    USE SIGNAL ;
    PORT
      LAYER met2 ;
        RECT 29.070 0.000 29.350 4.000 ;
    END
  END pmatrix_rowon_out_n[9]
  PIN result_out[0]
    DIRECTION OUTPUT TRISTATE ;
    USE SIGNAL ;
    PORT
      LAYER met2 ;
        RECT 9.750 0.000 10.030 4.000 ;
    END
  END result_out[0]
  PIN result_out[10]
    DIRECTION OUTPUT TRISTATE ;
    USE SIGNAL ;
    PORT
      LAYER met2 ;
        RECT 103.130 165.565 103.410 169.565 ;
    END
  END result_out[10]
  PIN result_out[11]
    DIRECTION OUTPUT TRISTATE ;
    USE SIGNAL ;
    PORT
      LAYER met2 ;
        RECT 70.930 165.565 71.210 169.565 ;
    END
  END result_out[11]
  PIN result_out[12]
    DIRECTION OUTPUT TRISTATE ;
    USE SIGNAL ;
    PORT
      LAYER met2 ;
        RECT 80.590 0.000 80.870 4.000 ;
    END
  END result_out[12]
  PIN result_out[13]
    DIRECTION OUTPUT TRISTATE ;
    USE SIGNAL ;
    PORT
      LAYER met2 ;
        RECT 128.890 165.565 129.170 169.565 ;
    END
  END result_out[13]
  PIN result_out[14]
    DIRECTION OUTPUT TRISTATE ;
    USE SIGNAL ;
    PORT
      LAYER met3 ;
        RECT 154.845 37.440 158.845 38.040 ;
    END
  END result_out[14]
  PIN result_out[15]
    DIRECTION OUTPUT TRISTATE ;
    USE SIGNAL ;
    PORT
      LAYER met3 ;
        RECT 0.000 132.640 4.000 133.240 ;
    END
  END result_out[15]
  PIN result_out[1]
    DIRECTION OUTPUT TRISTATE ;
    USE SIGNAL ;
    PORT
      LAYER met3 ;
        RECT 0.000 34.040 4.000 34.640 ;
    END
  END result_out[1]
  PIN result_out[2]
    DIRECTION OUTPUT TRISTATE ;
    USE SIGNAL ;
    PORT
      LAYER met2 ;
        RECT 32.290 0.000 32.570 4.000 ;
    END
  END result_out[2]
  PIN result_out[3]
    DIRECTION OUTPUT TRISTATE ;
    USE SIGNAL ;
    PORT
      LAYER met2 ;
        RECT 58.050 0.000 58.330 4.000 ;
    END
  END result_out[3]
  PIN result_out[4]
    DIRECTION OUTPUT TRISTATE ;
    USE SIGNAL ;
    PORT
      LAYER met3 ;
        RECT 0.000 30.640 4.000 31.240 ;
    END
  END result_out[4]
  PIN result_out[5]
    DIRECTION OUTPUT TRISTATE ;
    USE SIGNAL ;
    PORT
      LAYER met3 ;
        RECT 154.845 115.640 158.845 116.240 ;
    END
  END result_out[5]
  PIN result_out[6]
    DIRECTION OUTPUT TRISTATE ;
    USE SIGNAL ;
    PORT
      LAYER met2 ;
        RECT 93.470 0.000 93.750 4.000 ;
    END
  END result_out[6]
  PIN result_out[7]
    DIRECTION OUTPUT TRISTATE ;
    USE SIGNAL ;
    PORT
      LAYER met3 ;
        RECT 0.000 23.840 4.000 24.440 ;
    END
  END result_out[7]
  PIN result_out[8]
    DIRECTION OUTPUT TRISTATE ;
    USE SIGNAL ;
    PORT
      LAYER met2 ;
        RECT 109.570 165.565 109.850 169.565 ;
    END
  END result_out[8]
  PIN result_out[9]
    DIRECTION OUTPUT TRISTATE ;
    USE SIGNAL ;
    PORT
      LAYER met3 ;
        RECT 0.000 163.240 4.000 163.840 ;
    END
  END result_out[9]
  PIN rst_n
    DIRECTION INPUT ;
    USE SIGNAL ;
    PORT
      LAYER met2 ;
        RECT 19.410 165.565 19.690 169.565 ;
    END
  END rst_n
  PIN sample_matrix_out
    DIRECTION OUTPUT TRISTATE ;
    USE SIGNAL ;
    PORT
      LAYER met2 ;
        RECT 112.790 0.000 113.070 4.000 ;
    END
  END sample_matrix_out
  PIN sample_matrix_out_n
    DIRECTION OUTPUT TRISTATE ;
    USE SIGNAL ;
    PORT
      LAYER met3 ;
        RECT 0.000 40.840 4.000 41.440 ;
    END
  END sample_matrix_out_n
  PIN sample_switch_out
    DIRECTION OUTPUT TRISTATE ;
    USE SIGNAL ;
    PORT
      LAYER met3 ;
        RECT 0.000 142.840 4.000 143.440 ;
    END
  END sample_switch_out
  PIN sample_switch_out_n
    DIRECTION OUTPUT TRISTATE ;
    USE SIGNAL ;
    PORT
      LAYER met3 ;
        RECT 154.845 81.640 158.845 82.240 ;
    END
  END sample_switch_out_n
  OBS
      LAYER li1 ;
        RECT 5.520 10.795 153.180 157.845 ;
      LAYER met1 ;
        RECT 0.070 7.180 158.170 158.000 ;
      LAYER met2 ;
        RECT 0.650 165.285 3.030 167.125 ;
        RECT 3.870 165.285 6.250 167.125 ;
        RECT 7.090 165.285 9.470 167.125 ;
        RECT 10.310 165.285 12.690 167.125 ;
        RECT 13.530 165.285 15.910 167.125 ;
        RECT 16.750 165.285 19.130 167.125 ;
        RECT 19.970 165.285 25.570 167.125 ;
        RECT 26.410 165.285 28.790 167.125 ;
        RECT 29.630 165.285 32.010 167.125 ;
        RECT 32.850 165.285 35.230 167.125 ;
        RECT 36.070 165.285 38.450 167.125 ;
        RECT 39.290 165.285 41.670 167.125 ;
        RECT 42.510 165.285 44.890 167.125 ;
        RECT 45.730 165.285 48.110 167.125 ;
        RECT 48.950 165.285 51.330 167.125 ;
        RECT 52.170 165.285 54.550 167.125 ;
        RECT 55.390 165.285 57.770 167.125 ;
        RECT 58.610 165.285 60.990 167.125 ;
        RECT 61.830 165.285 64.210 167.125 ;
        RECT 65.050 165.285 67.430 167.125 ;
        RECT 68.270 165.285 70.650 167.125 ;
        RECT 71.490 165.285 73.870 167.125 ;
        RECT 74.710 165.285 77.090 167.125 ;
        RECT 77.930 165.285 80.310 167.125 ;
        RECT 81.150 165.285 83.530 167.125 ;
        RECT 84.370 165.285 86.750 167.125 ;
        RECT 87.590 165.285 89.970 167.125 ;
        RECT 90.810 165.285 93.190 167.125 ;
        RECT 94.030 165.285 96.410 167.125 ;
        RECT 97.250 165.285 99.630 167.125 ;
        RECT 100.470 165.285 102.850 167.125 ;
        RECT 103.690 165.285 106.070 167.125 ;
        RECT 106.910 165.285 109.290 167.125 ;
        RECT 110.130 165.285 115.730 167.125 ;
        RECT 116.570 165.285 118.950 167.125 ;
        RECT 119.790 165.285 122.170 167.125 ;
        RECT 123.010 165.285 125.390 167.125 ;
        RECT 126.230 165.285 128.610 167.125 ;
        RECT 129.450 165.285 131.830 167.125 ;
        RECT 132.670 165.285 135.050 167.125 ;
        RECT 135.890 165.285 138.270 167.125 ;
        RECT 139.110 165.285 141.490 167.125 ;
        RECT 142.330 165.285 144.710 167.125 ;
        RECT 145.550 165.285 147.930 167.125 ;
        RECT 148.770 165.285 151.150 167.125 ;
        RECT 151.990 165.285 154.370 167.125 ;
        RECT 155.210 165.285 157.590 167.125 ;
        RECT 0.100 4.280 158.140 165.285 ;
        RECT 0.650 3.555 3.030 4.280 ;
        RECT 3.870 3.555 6.250 4.280 ;
        RECT 7.090 3.555 9.470 4.280 ;
        RECT 10.310 3.555 12.690 4.280 ;
        RECT 13.530 3.555 15.910 4.280 ;
        RECT 16.750 3.555 19.130 4.280 ;
        RECT 19.970 3.555 22.350 4.280 ;
        RECT 23.190 3.555 25.570 4.280 ;
        RECT 26.410 3.555 28.790 4.280 ;
        RECT 29.630 3.555 32.010 4.280 ;
        RECT 32.850 3.555 35.230 4.280 ;
        RECT 36.070 3.555 38.450 4.280 ;
        RECT 39.290 3.555 41.670 4.280 ;
        RECT 42.510 3.555 44.890 4.280 ;
        RECT 45.730 3.555 48.110 4.280 ;
        RECT 48.950 3.555 51.330 4.280 ;
        RECT 52.170 3.555 54.550 4.280 ;
        RECT 55.390 3.555 57.770 4.280 ;
        RECT 58.610 3.555 60.990 4.280 ;
        RECT 61.830 3.555 64.210 4.280 ;
        RECT 65.050 3.555 67.430 4.280 ;
        RECT 68.270 3.555 70.650 4.280 ;
        RECT 71.490 3.555 73.870 4.280 ;
        RECT 74.710 3.555 77.090 4.280 ;
        RECT 77.930 3.555 80.310 4.280 ;
        RECT 81.150 3.555 83.530 4.280 ;
        RECT 84.370 3.555 86.750 4.280 ;
        RECT 87.590 3.555 93.190 4.280 ;
        RECT 94.030 3.555 96.410 4.280 ;
        RECT 97.250 3.555 99.630 4.280 ;
        RECT 100.470 3.555 102.850 4.280 ;
        RECT 103.690 3.555 106.070 4.280 ;
        RECT 106.910 3.555 109.290 4.280 ;
        RECT 110.130 3.555 112.510 4.280 ;
        RECT 113.350 3.555 115.730 4.280 ;
        RECT 116.570 3.555 118.950 4.280 ;
        RECT 119.790 3.555 122.170 4.280 ;
        RECT 123.010 3.555 125.390 4.280 ;
        RECT 126.230 3.555 128.610 4.280 ;
        RECT 129.450 3.555 131.830 4.280 ;
        RECT 132.670 3.555 135.050 4.280 ;
        RECT 135.890 3.555 138.270 4.280 ;
        RECT 139.110 3.555 141.490 4.280 ;
        RECT 142.330 3.555 144.710 4.280 ;
        RECT 145.550 3.555 147.930 4.280 ;
        RECT 148.770 3.555 151.150 4.280 ;
        RECT 151.990 3.555 154.370 4.280 ;
        RECT 155.210 3.555 157.590 4.280 ;
      LAYER met3 ;
        RECT 4.400 166.240 154.445 167.105 ;
        RECT 4.000 164.240 154.845 166.240 ;
        RECT 4.400 162.840 154.445 164.240 ;
        RECT 4.000 160.840 154.845 162.840 ;
        RECT 4.400 159.440 154.445 160.840 ;
        RECT 4.000 157.440 154.845 159.440 ;
        RECT 4.400 156.040 154.445 157.440 ;
        RECT 4.000 154.040 154.845 156.040 ;
        RECT 4.400 152.640 154.445 154.040 ;
        RECT 4.000 150.640 154.845 152.640 ;
        RECT 4.400 149.240 154.445 150.640 ;
        RECT 4.000 147.240 154.845 149.240 ;
        RECT 4.400 145.840 154.445 147.240 ;
        RECT 4.000 143.840 154.845 145.840 ;
        RECT 4.400 142.440 154.445 143.840 ;
        RECT 4.000 140.440 154.845 142.440 ;
        RECT 4.400 139.040 154.445 140.440 ;
        RECT 4.000 137.040 154.845 139.040 ;
        RECT 4.400 135.640 154.445 137.040 ;
        RECT 4.000 133.640 154.845 135.640 ;
        RECT 4.400 132.240 154.445 133.640 ;
        RECT 4.000 130.240 154.845 132.240 ;
        RECT 4.400 128.840 154.445 130.240 ;
        RECT 4.000 126.840 154.845 128.840 ;
        RECT 4.400 125.440 154.445 126.840 ;
        RECT 4.000 123.440 154.845 125.440 ;
        RECT 4.400 122.040 154.445 123.440 ;
        RECT 4.000 120.040 154.845 122.040 ;
        RECT 4.400 118.640 154.845 120.040 ;
        RECT 4.000 116.640 154.845 118.640 ;
        RECT 4.400 115.240 154.445 116.640 ;
        RECT 4.000 113.240 154.845 115.240 ;
        RECT 4.400 111.840 154.445 113.240 ;
        RECT 4.000 109.840 154.845 111.840 ;
        RECT 4.400 108.440 154.445 109.840 ;
        RECT 4.000 106.440 154.845 108.440 ;
        RECT 4.400 105.040 154.445 106.440 ;
        RECT 4.000 103.040 154.845 105.040 ;
        RECT 4.400 101.640 154.445 103.040 ;
        RECT 4.000 99.640 154.845 101.640 ;
        RECT 4.400 98.240 154.445 99.640 ;
        RECT 4.000 96.240 154.845 98.240 ;
        RECT 4.000 94.840 154.445 96.240 ;
        RECT 4.000 92.840 154.845 94.840 ;
        RECT 4.400 91.440 154.445 92.840 ;
        RECT 4.000 89.440 154.845 91.440 ;
        RECT 4.400 88.040 154.445 89.440 ;
        RECT 4.000 86.040 154.845 88.040 ;
        RECT 4.400 84.640 154.445 86.040 ;
        RECT 4.000 82.640 154.845 84.640 ;
        RECT 4.400 81.240 154.445 82.640 ;
        RECT 4.000 79.240 154.845 81.240 ;
        RECT 4.400 77.840 154.445 79.240 ;
        RECT 4.000 75.840 154.845 77.840 ;
        RECT 4.400 74.440 154.445 75.840 ;
        RECT 4.000 72.440 154.845 74.440 ;
        RECT 4.400 71.040 154.445 72.440 ;
        RECT 4.000 69.040 154.845 71.040 ;
        RECT 4.400 67.640 154.445 69.040 ;
        RECT 4.000 65.640 154.845 67.640 ;
        RECT 4.400 64.240 154.445 65.640 ;
        RECT 4.000 62.240 154.845 64.240 ;
        RECT 4.400 60.840 154.445 62.240 ;
        RECT 4.000 58.840 154.845 60.840 ;
        RECT 4.400 57.440 154.445 58.840 ;
        RECT 4.000 55.440 154.845 57.440 ;
        RECT 4.400 54.040 154.445 55.440 ;
        RECT 4.000 52.040 154.845 54.040 ;
        RECT 4.400 50.640 154.445 52.040 ;
        RECT 4.000 48.640 154.845 50.640 ;
        RECT 4.400 47.240 154.445 48.640 ;
        RECT 4.000 45.240 154.845 47.240 ;
        RECT 4.400 43.840 154.445 45.240 ;
        RECT 4.000 41.840 154.845 43.840 ;
        RECT 4.400 40.440 154.445 41.840 ;
        RECT 4.000 38.440 154.845 40.440 ;
        RECT 4.400 37.040 154.445 38.440 ;
        RECT 4.000 35.040 154.845 37.040 ;
        RECT 4.400 33.640 154.445 35.040 ;
        RECT 4.000 31.640 154.845 33.640 ;
        RECT 4.400 30.240 154.445 31.640 ;
        RECT 4.000 28.240 154.845 30.240 ;
        RECT 4.400 26.840 154.445 28.240 ;
        RECT 4.000 24.840 154.845 26.840 ;
        RECT 4.400 23.440 154.845 24.840 ;
        RECT 4.000 21.440 154.845 23.440 ;
        RECT 4.400 20.040 154.445 21.440 ;
        RECT 4.000 18.040 154.845 20.040 ;
        RECT 4.400 16.640 154.445 18.040 ;
        RECT 4.000 14.640 154.845 16.640 ;
        RECT 4.400 13.240 154.445 14.640 ;
        RECT 4.000 11.240 154.845 13.240 ;
        RECT 4.400 9.840 154.445 11.240 ;
        RECT 4.000 7.840 154.845 9.840 ;
        RECT 4.400 6.440 154.445 7.840 ;
        RECT 4.000 4.440 154.845 6.440 ;
        RECT 4.400 3.575 154.445 4.440 ;
      LAYER met4 ;
        RECT 26.055 19.895 32.000 153.505 ;
        RECT 34.400 19.895 59.690 153.505 ;
        RECT 62.090 19.895 68.915 153.505 ;
        RECT 71.315 19.895 96.605 153.505 ;
        RECT 99.005 19.895 105.830 153.505 ;
        RECT 108.230 19.895 133.520 153.505 ;
        RECT 135.920 19.895 142.745 153.505 ;
        RECT 145.145 19.895 153.345 153.505 ;
  END
END adc_core_digital
END LIBRARY

